VERSION 5.8 ;
BUSBITCHARS "[]" ;
DIVIDERCHAR "/" ;
UNITS
    DATABASE MICRONS 1000 ;
END UNITS

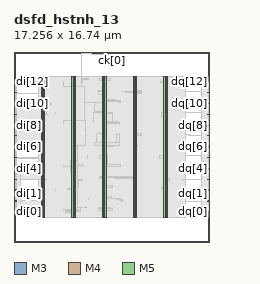
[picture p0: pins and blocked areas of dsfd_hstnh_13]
MACRO dsfd_hstnh_13
  FOREIGN dsfd_hstnh_13 0 0 ;
  CLASS BLOCK ;
  SIZE 17.256 BY 16.74 ;
  PIN ck[0]
    DIRECTION INPUT ;
    USE SIGNAL ;
    PORT
      LAYER M3 ;
        RECT  8.604 16.596 8.622 16.74 ;
    END
  END ck[0]
  PIN di[0]
    DIRECTION INPUT ;
    USE SIGNAL ;
    PORT
      LAYER M4 ;
        RECT  0 2.64 0.192 2.664 ;
    END
  END di[0]
  PIN di[10]
    DIRECTION INPUT ;
    USE SIGNAL ;
    PORT
      LAYER M4 ;
        RECT  0 12.192 0.192 12.216 ;
    END
  END di[10]
  PIN di[11]
    DIRECTION INPUT ;
    USE SIGNAL ;
    PORT
      LAYER M4 ;
        RECT  0 13.152 0.192 13.176 ;
    END
  END di[11]
  PIN di[12]
    DIRECTION INPUT ;
    USE SIGNAL ;
    PORT
      LAYER M4 ;
        RECT  0 14.112 0.192 14.136 ;
    END
  END di[12]
  PIN di[1]
    DIRECTION INPUT ;
    USE SIGNAL ;
    PORT
      LAYER M4 ;
        RECT  0 3.6 0.192 3.624 ;
    END
  END di[1]
  PIN di[2]
    DIRECTION INPUT ;
    USE SIGNAL ;
    PORT
      LAYER M4 ;
        RECT  0 4.56 0.192 4.584 ;
    END
  END di[2]
  PIN di[3]
    DIRECTION INPUT ;
    USE SIGNAL ;
    PORT
      LAYER M4 ;
        RECT  0 5.52 0.192 5.544 ;
    END
  END di[3]
  PIN di[4]
    DIRECTION INPUT ;
    USE SIGNAL ;
    PORT
      LAYER M4 ;
        RECT  0 6.48 0.192 6.504 ;
    END
  END di[4]
  PIN di[5]
    DIRECTION INPUT ;
    USE SIGNAL ;
    PORT
      LAYER M4 ;
        RECT  0 7.44 0.192 7.464 ;
    END
  END di[5]
  PIN di[6]
    DIRECTION INPUT ;
    USE SIGNAL ;
    PORT
      LAYER M4 ;
        RECT  0 8.4 0.192 8.424 ;
    END
  END di[6]
  PIN di[7]
    DIRECTION INPUT ;
    USE SIGNAL ;
    PORT
      LAYER M4 ;
        RECT  0 9.36 0.192 9.384 ;
    END
  END di[7]
  PIN di[8]
    DIRECTION INPUT ;
    USE SIGNAL ;
    PORT
      LAYER M4 ;
        RECT  0 10.272 0.192 10.296 ;
    END
  END di[8]
  PIN di[9]
    DIRECTION INPUT ;
    USE SIGNAL ;
    PORT
      LAYER M4 ;
        RECT  0 11.232 0.192 11.256 ;
    END
  END di[9]
  PIN dq[0]
    DIRECTION OUTPUT ;
    USE SIGNAL ;
    PORT
      LAYER M4 ;
        RECT  17.064 2.64 17.256 2.664 ;
    END
  END dq[0]
  PIN dq[10]
    DIRECTION OUTPUT ;
    USE SIGNAL ;
    PORT
      LAYER M4 ;
        RECT  17.064 12.192 17.256 12.216 ;
    END
  END dq[10]
  PIN dq[11]
    DIRECTION OUTPUT ;
    USE SIGNAL ;
    PORT
      LAYER M4 ;
        RECT  17.064 13.152 17.256 13.176 ;
    END
  END dq[11]
  PIN dq[12]
    DIRECTION OUTPUT ;
    USE SIGNAL ;
    PORT
      LAYER M4 ;
        RECT  17.064 14.112 17.256 14.136 ;
    END
  END dq[12]
  PIN dq[1]
    DIRECTION OUTPUT ;
    USE SIGNAL ;
    PORT
      LAYER M4 ;
        RECT  17.064 3.6 17.256 3.624 ;
    END
  END dq[1]
  PIN dq[2]
    DIRECTION OUTPUT ;
    USE SIGNAL ;
    PORT
      LAYER M4 ;
        RECT  17.064 4.56 17.256 4.584 ;
    END
  END dq[2]
  PIN dq[3]
    DIRECTION OUTPUT ;
    USE SIGNAL ;
    PORT
      LAYER M4 ;
        RECT  17.064 5.52 17.256 5.544 ;
    END
  END dq[3]
  PIN dq[4]
    DIRECTION OUTPUT ;
    USE SIGNAL ;
    PORT
      LAYER M4 ;
        RECT  17.064 6.48 17.256 6.504 ;
    END
  END dq[4]
  PIN dq[5]
    DIRECTION OUTPUT ;
    USE SIGNAL ;
    PORT
      LAYER M4 ;
        RECT  17.064 7.44 17.256 7.464 ;
    END
  END dq[5]
  PIN dq[6]
    DIRECTION OUTPUT ;
    USE SIGNAL ;
    PORT
      LAYER M4 ;
        RECT  17.064 8.4 17.256 8.424 ;
    END
  END dq[6]
  PIN dq[7]
    DIRECTION OUTPUT ;
    USE SIGNAL ;
    PORT
      LAYER M4 ;
        RECT  17.064 9.36 17.256 9.384 ;
    END
  END dq[7]
  PIN dq[8]
    DIRECTION OUTPUT ;
    USE SIGNAL ;
    PORT
      LAYER M4 ;
        RECT  17.064 10.272 17.256 10.296 ;
    END
  END dq[8]
  PIN dq[9]
    DIRECTION OUTPUT ;
    USE SIGNAL ;
    PORT
      LAYER M4 ;
        RECT  17.064 11.232 17.256 11.256 ;
    END
  END dq[9]
  PIN VDD
    DIRECTION INOUT ;
    USE POWER ;
    PORT
      LAYER M5 ;
        RECT  13.392 2.151 13.512 14.589 ;
        RECT  10.692 2.151 10.812 14.589 ;
        RECT  7.992 2.151 8.112 14.589 ;
        RECT  5.292 2.151 5.412 14.589 ;
        RECT  2.592 2.151 2.712 14.589 ;
    END
  END VDD
  PIN VSS
    DIRECTION INOUT ;
    USE GROUND ;
    PORT
      LAYER M5 ;
        RECT  13.2 2.137 13.32 14.603 ;
        RECT  10.5 2.137 10.62 14.603 ;
        RECT  7.8 2.137 7.92 14.603 ;
        RECT  5.1 2.137 5.22 14.603 ;
        RECT  2.4 2.137 2.52 14.603 ;
    END
  END VSS
  OBS
    LAYER RVTN ;
     RECT  2.16 2.16 15.066 2.295 ;
     RECT  2.16 2.565 15.066 2.835 ;
     RECT  2.16 3.105 15.066 3.375 ;
     RECT  2.16 3.645 15.066 3.915 ;
     RECT  2.16 4.185 15.066 4.455 ;
     RECT  2.16 4.725 15.066 4.995 ;
     RECT  2.16 5.265 15.066 5.535 ;
     RECT  2.16 5.805 15.066 6.075 ;
     RECT  2.16 6.345 15.066 6.615 ;
     RECT  2.16 6.885 15.066 7.155 ;
     RECT  2.16 7.425 15.066 7.695 ;
     RECT  2.16 7.965 15.066 8.235 ;
     RECT  2.16 8.505 15.066 8.775 ;
     RECT  2.16 9.045 15.066 9.315 ;
     RECT  2.16 9.585 15.066 9.855 ;
     RECT  2.16 10.125 15.066 10.395 ;
     RECT  2.16 10.665 15.066 10.935 ;
     RECT  2.16 11.205 15.066 11.475 ;
     RECT  2.16 11.745 15.066 12.015 ;
     RECT  2.16 12.285 15.066 12.555 ;
     RECT  2.16 12.825 15.066 13.095 ;
     RECT  2.16 13.365 15.066 13.635 ;
     RECT  2.16 13.905 15.066 14.175 ;
     RECT  2.16 14.445 15.066 14.58 ;
    LAYER RVTP ;
     RECT  2.16 2.295 15.066 2.565 ;
     RECT  2.16 2.835 15.066 3.105 ;
     RECT  2.16 3.375 15.066 3.645 ;
     RECT  2.16 3.915 15.066 4.185 ;
     RECT  2.16 4.455 15.066 4.725 ;
     RECT  2.16 4.995 15.066 5.265 ;
     RECT  2.16 5.535 15.066 5.805 ;
     RECT  2.16 6.075 15.066 6.345 ;
     RECT  2.16 6.615 15.066 6.885 ;
     RECT  2.16 7.155 15.066 7.425 ;
     RECT  2.16 7.695 15.066 7.965 ;
     RECT  2.16 8.235 15.066 8.505 ;
     RECT  2.16 8.775 15.066 9.045 ;
     RECT  2.16 9.315 15.066 9.585 ;
     RECT  2.16 9.855 15.066 10.125 ;
     RECT  2.16 10.395 15.066 10.665 ;
     RECT  2.16 10.935 15.066 11.205 ;
     RECT  2.16 11.475 15.066 11.745 ;
     RECT  2.16 12.015 15.066 12.285 ;
     RECT  2.16 12.555 15.066 12.825 ;
     RECT  2.16 13.095 15.066 13.365 ;
     RECT  2.16 13.635 15.066 13.905 ;
     RECT  2.16 14.175 15.066 14.445 ;
    LAYER M1 ;
     RECT  2.16 2.151 15.066 14.589 ;
    LAYER M2 ;
     RECT  0.535 4.5 2.16 4.518 ;
     RECT  0.211 7.398 2.16 7.416 ;
     RECT  0.211 13.068 2.16 13.086 ;
     RECT  2.16 2.151 15.066 14.589 ;
     RECT  15.066 9.486 15.431 9.504 ;
     RECT  15.066 13.266 16.511 13.284 ;
     RECT  15.066 2.736 16.547 2.754 ;
     RECT  15.066 3.546 16.547 3.564 ;
     RECT  15.066 4.626 16.547 4.644 ;
     RECT  15.066 6.516 16.547 6.534 ;
     RECT  15.066 7.596 16.547 7.614 ;
     RECT  15.066 8.442 16.547 8.46 ;
     RECT  15.066 10.296 16.547 10.314 ;
     RECT  15.066 11.376 16.547 11.394 ;
     RECT  15.066 12.222 16.547 12.24 ;
     RECT  15.066 14.076 16.547 14.094 ;
    LAYER M3 ;
     RECT  2.415 2.143 2.505 2.413 ;
     RECT  5.115 2.143 5.205 2.413 ;
     RECT  7.815 2.143 7.905 2.413 ;
     RECT  10.515 2.143 10.605 2.413 ;
     RECT  13.215 2.143 13.305 2.413 ;
     RECT  2.415 2.413 2.697 2.605 ;
     RECT  5.115 2.413 5.397 2.641 ;
     RECT  2.304 2.605 2.697 2.669 ;
     RECT  4.5 2.641 5.397 2.731 ;
     RECT  4.5 2.731 5.886 2.759 ;
     RECT  16.524 2.635 16.542 2.759 ;
     RECT  7.815 2.413 8.097 2.767 ;
     RECT  7.815 2.767 8.658 2.803 ;
     RECT  4.356 2.767 4.374 2.861 ;
     RECT  7.416 2.803 8.658 2.939 ;
     RECT  5.115 2.759 5.886 3.001 ;
     RECT  7.416 2.939 8.478 3.029 ;
     RECT  5.115 3.001 6.354 3.065 ;
     RECT  6.336 3.065 6.354 3.101 ;
     RECT  2.415 2.669 2.697 3.595 ;
     RECT  5.115 3.065 5.598 3.605 ;
     RECT  16.524 3.541 16.542 3.629 ;
     RECT  2.304 3.595 2.697 3.641 ;
     RECT  9.504 3.577 9.522 3.685 ;
     RECT  9.324 3.685 9.522 3.721 ;
     RECT  9.036 3.721 9.522 3.749 ;
     RECT  7.815 3.029 8.154 3.811 ;
     RECT  9.036 3.749 9.342 3.811 ;
     RECT  7.815 3.811 9.342 3.839 ;
     RECT  6.552 3.721 6.57 3.875 ;
     RECT  7.815 3.839 9.27 3.875 ;
     RECT  7.815 3.875 8.586 3.983 ;
     RECT  0.54 4.495 0.558 4.589 ;
     RECT  5.115 3.605 5.397 4.621 ;
     RECT  13.215 2.413 13.497 4.621 ;
     RECT  3.636 4.531 3.654 4.649 ;
     RECT  16.524 4.555 16.542 4.649 ;
     RECT  4.752 4.621 5.397 4.685 ;
     RECT  7.815 3.983 8.097 4.765 ;
     RECT  12.996 4.621 13.497 4.793 ;
     RECT  5.115 4.685 5.397 4.801 ;
     RECT  7.815 4.765 8.694 4.955 ;
     RECT  5.115 4.801 5.706 5.419 ;
     RECT  13.215 4.793 13.497 5.431 ;
     RECT  5.115 5.419 6.03 5.495 ;
     RECT  2.415 3.641 2.697 5.503 ;
     RECT  2.415 5.503 2.826 5.549 ;
     RECT  14.832 5.431 14.85 5.549 ;
     RECT  10.515 2.413 10.797 5.575 ;
     RECT  13.215 5.431 13.662 5.603 ;
     RECT  7.815 4.955 8.097 5.611 ;
     RECT  9.792 5.575 10.797 5.611 ;
     RECT  7.524 5.611 8.097 5.701 ;
     RECT  8.856 5.611 10.797 5.701 ;
     RECT  7.524 5.701 10.797 5.729 ;
     RECT  7.524 5.729 8.226 5.765 ;
     RECT  9.576 5.729 9.594 5.765 ;
     RECT  7.815 5.765 8.226 5.801 ;
     RECT  5.115 5.495 5.397 6.385 ;
     RECT  2.415 5.549 2.697 6.475 ;
     RECT  16.524 6.475 16.542 6.539 ;
     RECT  2.304 6.475 2.697 6.575 ;
     RECT  5.115 6.385 5.562 6.691 ;
     RECT  7.815 5.801 8.097 6.691 ;
     RECT  9.36 6.655 9.378 6.691 ;
     RECT  4.356 6.655 4.374 6.701 ;
     RECT  7.815 6.691 9.378 6.809 ;
     RECT  5.115 6.691 6.138 6.845 ;
     RECT  9.108 6.809 9.126 6.845 ;
     RECT  5.115 6.845 5.397 7.099 ;
     RECT  13.215 5.603 13.497 7.321 ;
     RECT  5.112 7.099 5.397 7.385 ;
     RECT  7.815 6.809 8.226 7.393 ;
     RECT  0.216 7.393 0.234 7.469 ;
     RECT  7.524 7.393 8.226 7.619 ;
     RECT  16.524 7.435 16.542 7.619 ;
     RECT  6.444 7.321 6.462 7.655 ;
     RECT  12.816 7.321 13.497 7.655 ;
     RECT  2.415 6.575 2.697 8.395 ;
     RECT  7.815 7.619 8.097 8.401 ;
     RECT  10.515 5.729 10.797 8.401 ;
     RECT  13.215 7.655 13.497 8.437 ;
     RECT  2.304 8.395 2.697 8.465 ;
     RECT  16.524 8.395 16.542 8.465 ;
     RECT  5.115 7.385 5.397 8.491 ;
     RECT  10.515 8.401 10.854 8.501 ;
     RECT  7.815 8.401 8.73 8.509 ;
     RECT  5.115 8.491 5.814 8.537 ;
     RECT  13.215 8.437 13.518 8.609 ;
     RECT  7.092 8.509 9.27 8.735 ;
     RECT  5.115 8.537 5.778 9.101 ;
     RECT  10.515 8.501 10.797 9.355 ;
     RECT  6.336 9.349 6.354 9.389 ;
     RECT  10.515 9.355 11.07 9.391 ;
     RECT  9.036 8.735 9.27 9.509 ;
     RECT  15.408 9.355 15.426 9.509 ;
     RECT  7.308 8.735 8.097 9.545 ;
     RECT  9.252 9.509 9.27 9.545 ;
     RECT  10.515 9.391 11.25 9.545 ;
     RECT  2.415 8.465 2.697 10.267 ;
     RECT  16.524 10.267 16.542 10.319 ;
     RECT  2.304 10.267 2.697 10.355 ;
     RECT  9.288 10.327 9.306 10.435 ;
     RECT  7.815 9.545 8.097 10.471 ;
     RECT  9.108 10.435 9.306 10.471 ;
     RECT  7.815 10.471 9.306 10.499 ;
     RECT  7.815 10.499 9.126 10.589 ;
     RECT  6.192 10.471 6.21 10.625 ;
     RECT  7.815 10.589 8.946 10.625 ;
     RECT  5.115 9.101 5.397 10.699 ;
     RECT  4.356 10.435 4.374 10.733 ;
     RECT  13.215 8.609 13.497 11.101 ;
     RECT  2.415 10.355 2.697 11.227 ;
     RECT  7.815 10.625 8.694 11.281 ;
     RECT  6.984 10.561 7.002 11.371 ;
     RECT  7.776 11.281 8.694 11.371 ;
     RECT  3.636 11.281 3.654 11.399 ;
     RECT  6.984 11.371 8.694 11.399 ;
     RECT  16.524 11.227 16.542 11.399 ;
     RECT  5.115 10.699 6.03 11.405 ;
     RECT  6.984 11.399 8.37 11.435 ;
     RECT  12.996 11.101 13.497 11.435 ;
     RECT  5.115 11.405 5.706 11.453 ;
     RECT  7.056 11.435 8.097 11.471 ;
     RECT  2.415 11.227 2.898 12.091 ;
     RECT  2.415 12.091 3.33 12.187 ;
     RECT  2.34 12.187 3.33 12.209 ;
     RECT  7.056 11.471 7.074 12.209 ;
     RECT  13.215 11.435 13.497 12.217 ;
     RECT  2.34 12.209 2.697 12.245 ;
     RECT  16.524 12.187 16.542 12.245 ;
     RECT  6.876 12.28 6.894 12.317 ;
     RECT  7.815 11.471 8.097 12.361 ;
     RECT  9.324 12.325 9.342 12.361 ;
     RECT  13.215 12.217 13.518 12.389 ;
     RECT  7.815 12.361 9.342 12.479 ;
     RECT  7.815 12.479 8.982 12.515 ;
     RECT  7.815 12.515 8.55 12.551 ;
     RECT  7.815 12.551 8.097 12.991 ;
     RECT  10.515 9.545 10.797 13.063 ;
     RECT  6.192 13.027 6.21 13.085 ;
     RECT  10.515 13.063 11.214 13.171 ;
     RECT  0.216 13.063 0.234 13.181 ;
     RECT  9.792 13.171 11.214 13.261 ;
     RECT  9.576 13.261 11.214 13.289 ;
     RECT  16.488 13.147 16.506 13.289 ;
     RECT  7.416 12.991 8.097 13.297 ;
     RECT  7.416 13.297 8.118 13.325 ;
     RECT  10.515 13.289 11.214 13.325 ;
     RECT  9.576 13.289 9.594 13.361 ;
     RECT  7.815 13.325 8.118 13.469 ;
     RECT  5.115 11.453 5.397 14.071 ;
     RECT  13.215 12.389 13.497 14.071 ;
     RECT  4.356 13.675 4.374 14.135 ;
     RECT  16.524 14.071 16.542 14.141 ;
     RECT  12.924 14.071 13.497 14.171 ;
     RECT  7.815 13.469 8.097 14.215 ;
     RECT  7.815 14.215 8.514 14.251 ;
     RECT  2.415 12.245 2.697 14.327 ;
     RECT  5.115 14.071 5.994 14.327 ;
     RECT  10.515 13.325 10.797 14.327 ;
     RECT  13.215 14.171 13.497 14.327 ;
     RECT  5.976 14.327 5.994 14.341 ;
     RECT  7.524 14.251 8.514 14.369 ;
     RECT  5.976 14.341 6.57 14.405 ;
     RECT  7.815 14.369 8.298 14.405 ;
     RECT  6.552 14.405 6.57 14.441 ;
     RECT  2.415 14.327 2.505 14.597 ;
     RECT  5.115 14.327 5.205 14.597 ;
     RECT  7.815 14.405 7.905 14.597 ;
     RECT  10.515 14.327 10.605 14.597 ;
     RECT  13.215 14.327 13.305 14.597 ;
     RECT  8.604 16.507 8.622 16.62 ;
     RECT  6.84 16.507 6.858 16.637 ;
    LAYER M4 ;
     RECT  0.156 2.64 0.245 14.136 ;
     RECT  0.245 2.64 0.569 6.504 ;
     RECT  0.569 2.64 2.408 3.624 ;
     RECT  0.569 5.52 2.408 6.504 ;
     RECT  0.245 8.4 2.408 12.216 ;
     RECT  0.245 14.112 2.408 14.136 ;
     RECT  2.408 2.148 2.512 14.592 ;
     RECT  2.512 2.418 2.704 14.322 ;
     RECT  2.704 5.52 2.837 5.544 ;
     RECT  2.704 11.232 2.909 11.256 ;
     RECT  4.345 6.672 4.981 6.696 ;
     RECT  4.345 2.832 5.108 2.856 ;
     RECT  4.741 4.656 5.108 4.68 ;
     RECT  4.981 6.24 5.108 7.128 ;
     RECT  4.345 10.704 5.108 10.728 ;
     RECT  4.345 13.68 5.108 13.704 ;
     RECT  5.108 2.148 5.212 14.592 ;
     RECT  5.212 2.418 5.404 14.322 ;
     RECT  5.404 2.832 5.603 3.576 ;
     RECT  5.404 4.656 5.603 6.84 ;
     RECT  5.603 6.816 5.617 6.84 ;
     RECT  5.603 3.552 5.644 3.576 ;
     RECT  5.603 5.424 6.041 5.448 ;
     RECT  5.404 10.704 6.179 13.704 ;
     RECT  6.179 12.288 6.221 13.08 ;
     RECT  5.404 8.496 6.275 9.384 ;
     RECT  6.179 10.704 6.275 10.728 ;
     RECT  6.275 9.36 6.365 9.384 ;
     RECT  5.941 16.608 6.829 16.632 ;
     RECT  6.829 16.512 6.869 16.632 ;
     RECT  6.221 12.288 7.808 12.312 ;
     RECT  7.808 2.148 7.912 14.592 ;
     RECT  7.912 2.418 8.104 14.322 ;
     RECT  6.869 16.512 8.633 16.536 ;
     RECT  10.508 2.148 10.612 14.592 ;
     RECT  10.612 2.418 10.804 14.322 ;
     RECT  13.208 2.148 13.312 14.592 ;
     RECT  13.312 2.418 13.504 14.322 ;
     RECT  14.821 5.52 16.513 5.544 ;
     RECT  15.397 9.36 16.513 9.384 ;
     RECT  16.477 13.152 16.513 13.176 ;
     RECT  16.513 2.64 17.1 14.136 ;
    LAYER M5 ;
     RECT  2.4 2.137 2.52 2.151 ;
     RECT  5.1 2.137 5.22 2.151 ;
     RECT  7.8 2.137 7.92 2.151 ;
     RECT  10.5 2.137 10.62 2.151 ;
     RECT  13.2 2.137 13.32 2.151 ;
     RECT  5.1 2.151 5.412 2.821 ;
     RECT  5.1 2.821 5.592 6.229 ;
     RECT  4.992 6.229 5.592 7.139 ;
     RECT  5.1 7.139 5.592 8.485 ;
     RECT  5.1 8.485 6.264 10.739 ;
     RECT  5.1 10.739 6.168 13.715 ;
     RECT  2.4 2.151 2.712 14.589 ;
     RECT  7.8 2.151 8.112 14.589 ;
     RECT  10.5 2.151 10.812 14.589 ;
     RECT  13.2 2.151 13.512 14.589 ;
     RECT  2.4 14.589 2.52 14.603 ;
     RECT  5.1 13.715 5.976 14.603 ;
     RECT  7.8 14.589 7.92 14.603 ;
     RECT  10.5 14.589 10.62 14.603 ;
     RECT  13.2 14.589 13.32 14.603 ;
     RECT  5.952 14.603 5.976 16.643 ;
  END
END dsfd_hstnh_13
END LIBRARY
